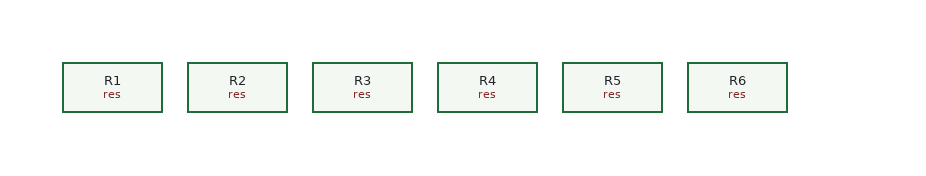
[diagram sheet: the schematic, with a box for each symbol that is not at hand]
v {xschem version=3.4.8RC file_version=1.3}
G {}
K {}
V {}
S {}
F {}
E {}
C {res.sym} 0 0 0 0 {name=R1 value=1 device_model=".model DA D (Is=1n)"}
C {res.sym} 100 0 0 0 {name=R2 value=1 device_model=".model QN NPN (bf=100)"}
C {res.sym} 200 0 0 0 {name=R3 value=1 device_model=".model NMA NMOS (level=1)"}
C {res.sym} 300 0 0 0 {name=R4 value=1 device_model=".model PMA PMOS (level=1)"}
C {res.sym} 400 0 0 0 {name=R5 value=1 device_model=".subckt zz a b"}
C {res.sym} 500 0 0 0 {name=R6 value=1 device_model=".model DA D (Is=7n)"}
